VERSION 5.8 ;
BUSBITCHARS "[]" ;
DIVIDERCHAR "/" ;
UNITS
    DATABASE MICRONS 1000 ;
END UNITS

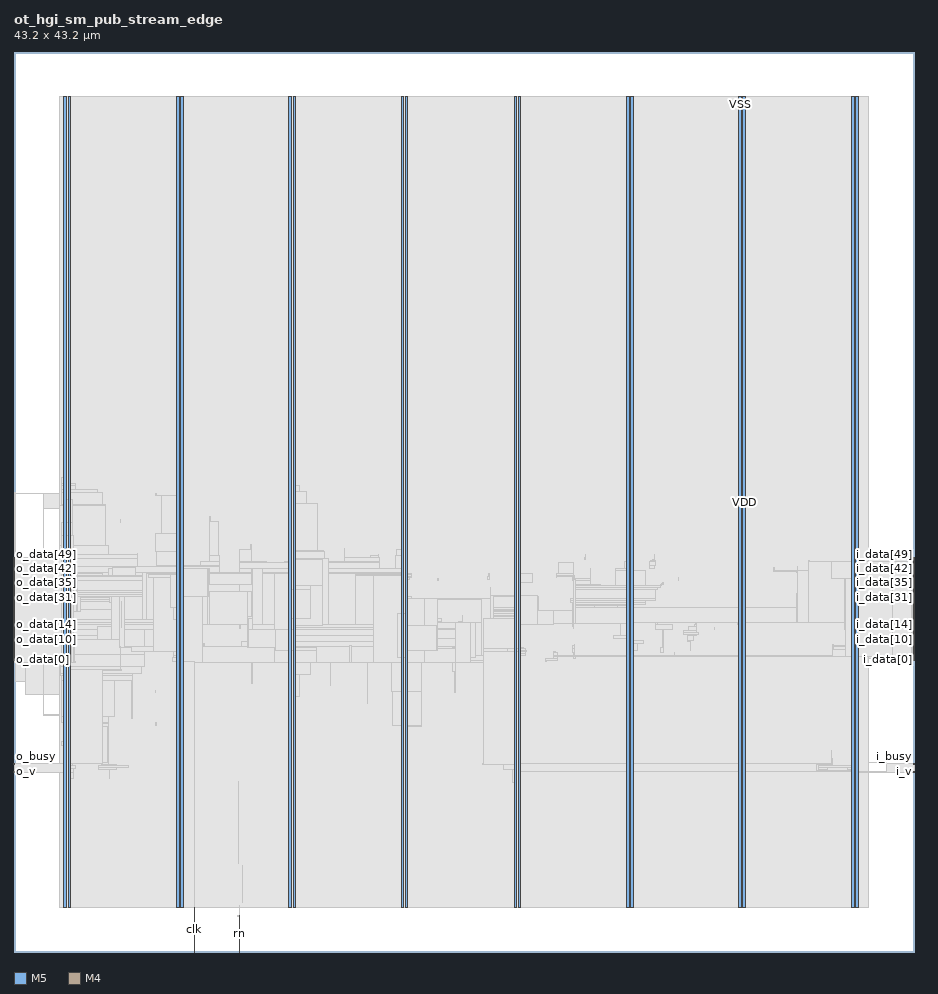
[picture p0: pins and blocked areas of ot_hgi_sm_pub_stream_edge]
MACRO ot_hgi_sm_pub_stream_edge
  FOREIGN ot_hgi_sm_pub_stream_edge 0 0 ;
  CLASS BLOCK ;
  SIZE 43.2 BY 43.2 ;
  PIN clk
    DIRECTION INPUT ;
    USE SIGNAL ;
    PORT
      LAYER M5 ;
        RECT  8.64 -0.042 8.664 0.042 ;
    END
    PORT
      LAYER M5 ;
        RECT  8.64 0.016 8.664 2.137 ;
    END
  END clk
  PIN i_busy
    DIRECTION INPUT ;
    USE SIGNAL ;
    PORT
      LAYER M4 ;
        RECT  43.158 9.024 43.242 9.048 ;
    END
  END i_busy
  PIN i_data[0]
    DIRECTION INPUT ;
    USE SIGNAL ;
    PORT
      LAYER M4 ;
        RECT  43.158 14.016 43.242 14.04 ;
    END
  END i_data[0]
  PIN i_data[10]
    DIRECTION INPUT ;
    USE SIGNAL ;
    PORT
      LAYER M4 ;
        RECT  43.158 14.976 43.242 15 ;
    END
  END i_data[10]
  PIN i_data[11]
    DIRECTION INPUT ;
    USE SIGNAL ;
    PORT
      LAYER M4 ;
        RECT  43.158 15.072 43.242 15.096 ;
    END
  END i_data[11]
  PIN i_data[12]
    DIRECTION INPUT ;
    USE SIGNAL ;
    PORT
      LAYER M4 ;
        RECT  43.158 15.168 43.242 15.192 ;
    END
  END i_data[12]
  PIN i_data[13]
    DIRECTION INPUT ;
    USE SIGNAL ;
    PORT
      LAYER M4 ;
        RECT  43.158 15.264 43.242 15.288 ;
    END
  END i_data[13]
  PIN i_data[14]
    DIRECTION INPUT ;
    USE SIGNAL ;
    PORT
      LAYER M4 ;
        RECT  43.158 15.36 43.242 15.384 ;
    END
  END i_data[14]
  PIN i_data[15]
    DIRECTION INPUT ;
    USE SIGNAL ;
    PORT
      LAYER M4 ;
        RECT  43.158 15.456 43.242 15.48 ;
    END
  END i_data[15]
  PIN i_data[16]
    DIRECTION INPUT ;
    USE SIGNAL ;
    PORT
      LAYER M4 ;
        RECT  43.158 15.552 43.242 15.576 ;
    END
  END i_data[16]
  PIN i_data[17]
    DIRECTION INPUT ;
    USE SIGNAL ;
    PORT
      LAYER M4 ;
        RECT  43.158 15.648 43.242 15.672 ;
    END
  END i_data[17]
  PIN i_data[18]
    DIRECTION INPUT ;
    USE SIGNAL ;
    PORT
      LAYER M4 ;
        RECT  43.158 15.744 43.242 15.768 ;
    END
  END i_data[18]
  PIN i_data[19]
    DIRECTION INPUT ;
    USE SIGNAL ;
    PORT
      LAYER M4 ;
        RECT  43.158 15.84 43.242 15.864 ;
    END
  END i_data[19]
  PIN i_data[1]
    DIRECTION INPUT ;
    USE SIGNAL ;
    PORT
      LAYER M4 ;
        RECT  43.158 14.112 43.242 14.136 ;
    END
  END i_data[1]
  PIN i_data[20]
    DIRECTION INPUT ;
    USE SIGNAL ;
    PORT
      LAYER M4 ;
        RECT  43.158 15.936 43.242 15.96 ;
    END
  END i_data[20]
  PIN i_data[21]
    DIRECTION INPUT ;
    USE SIGNAL ;
    PORT
      LAYER M4 ;
        RECT  43.158 16.032 43.242 16.056 ;
    END
  END i_data[21]
  PIN i_data[22]
    DIRECTION INPUT ;
    USE SIGNAL ;
    PORT
      LAYER M4 ;
        RECT  43.158 16.128 43.242 16.152 ;
    END
  END i_data[22]
  PIN i_data[23]
    DIRECTION INPUT ;
    USE SIGNAL ;
    PORT
      LAYER M4 ;
        RECT  43.158 16.224 43.242 16.248 ;
    END
  END i_data[23]
  PIN i_data[24]
    DIRECTION INPUT ;
    USE SIGNAL ;
    PORT
      LAYER M4 ;
        RECT  43.158 16.32 43.242 16.344 ;
    END
  END i_data[24]
  PIN i_data[25]
    DIRECTION INPUT ;
    USE SIGNAL ;
    PORT
      LAYER M4 ;
        RECT  43.158 16.416 43.242 16.44 ;
    END
  END i_data[25]
  PIN i_data[26]
    DIRECTION INPUT ;
    USE SIGNAL ;
    PORT
      LAYER M4 ;
        RECT  43.158 16.512 43.242 16.536 ;
    END
  END i_data[26]
  PIN i_data[27]
    DIRECTION INPUT ;
    USE SIGNAL ;
    PORT
      LAYER M4 ;
        RECT  43.158 16.608 43.242 16.632 ;
    END
  END i_data[27]
  PIN i_data[28]
    DIRECTION INPUT ;
    USE SIGNAL ;
    PORT
      LAYER M4 ;
        RECT  43.158 16.704 43.242 16.728 ;
    END
  END i_data[28]
  PIN i_data[29]
    DIRECTION INPUT ;
    USE SIGNAL ;
    PORT
      LAYER M4 ;
        RECT  43.158 16.8 43.242 16.824 ;
    END
  END i_data[29]
  PIN i_data[2]
    DIRECTION INPUT ;
    USE SIGNAL ;
    PORT
      LAYER M4 ;
        RECT  43.158 14.208 43.242 14.232 ;
    END
  END i_data[2]
  PIN i_data[30]
    DIRECTION INPUT ;
    USE SIGNAL ;
    PORT
      LAYER M4 ;
        RECT  43.158 16.896 43.242 16.92 ;
    END
  END i_data[30]
  PIN i_data[31]
    DIRECTION INPUT ;
    USE SIGNAL ;
    PORT
      LAYER M4 ;
        RECT  43.158 16.992 43.242 17.016 ;
    END
  END i_data[31]
  PIN i_data[32]
    DIRECTION INPUT ;
    USE SIGNAL ;
    PORT
      LAYER M4 ;
        RECT  43.158 17.088 43.242 17.112 ;
    END
  END i_data[32]
  PIN i_data[33]
    DIRECTION INPUT ;
    USE SIGNAL ;
    PORT
      LAYER M4 ;
        RECT  43.158 17.184 43.242 17.208 ;
    END
  END i_data[33]
  PIN i_data[34]
    DIRECTION INPUT ;
    USE SIGNAL ;
    PORT
      LAYER M4 ;
        RECT  43.158 17.28 43.242 17.304 ;
    END
  END i_data[34]
  PIN i_data[35]
    DIRECTION INPUT ;
    USE SIGNAL ;
    PORT
      LAYER M4 ;
        RECT  43.158 17.376 43.242 17.4 ;
    END
  END i_data[35]
  PIN i_data[36]
    DIRECTION INPUT ;
    USE SIGNAL ;
    PORT
      LAYER M4 ;
        RECT  43.158 17.472 43.242 17.496 ;
    END
  END i_data[36]
  PIN i_data[37]
    DIRECTION INPUT ;
    USE SIGNAL ;
    PORT
      LAYER M4 ;
        RECT  43.158 17.568 43.242 17.592 ;
    END
  END i_data[37]
  PIN i_data[38]
    DIRECTION INPUT ;
    USE SIGNAL ;
    PORT
      LAYER M4 ;
        RECT  43.158 17.664 43.242 17.688 ;
    END
  END i_data[38]
  PIN i_data[39]
    DIRECTION INPUT ;
    USE SIGNAL ;
    PORT
      LAYER M4 ;
        RECT  43.158 17.76 43.242 17.784 ;
    END
  END i_data[39]
  PIN i_data[3]
    DIRECTION INPUT ;
    USE SIGNAL ;
    PORT
      LAYER M4 ;
        RECT  43.158 14.304 43.242 14.328 ;
    END
  END i_data[3]
  PIN i_data[40]
    DIRECTION INPUT ;
    USE SIGNAL ;
    PORT
      LAYER M4 ;
        RECT  43.158 17.856 43.242 17.88 ;
    END
  END i_data[40]
  PIN i_data[41]
    DIRECTION INPUT ;
    USE SIGNAL ;
    PORT
      LAYER M4 ;
        RECT  43.158 17.952 43.242 17.976 ;
    END
  END i_data[41]
  PIN i_data[42]
    DIRECTION INPUT ;
    USE SIGNAL ;
    PORT
      LAYER M4 ;
        RECT  43.158 18.048 43.242 18.072 ;
    END
  END i_data[42]
  PIN i_data[43]
    DIRECTION INPUT ;
    USE SIGNAL ;
    PORT
      LAYER M4 ;
        RECT  43.158 18.144 43.242 18.168 ;
    END
  END i_data[43]
  PIN i_data[44]
    DIRECTION INPUT ;
    USE SIGNAL ;
    PORT
      LAYER M4 ;
        RECT  43.158 18.24 43.242 18.264 ;
    END
  END i_data[44]
  PIN i_data[45]
    DIRECTION INPUT ;
    USE SIGNAL ;
    PORT
      LAYER M4 ;
        RECT  43.158 18.336 43.242 18.36 ;
    END
  END i_data[45]
  PIN i_data[46]
    DIRECTION INPUT ;
    USE SIGNAL ;
    PORT
      LAYER M4 ;
        RECT  43.158 18.432 43.242 18.456 ;
    END
  END i_data[46]
  PIN i_data[47]
    DIRECTION INPUT ;
    USE SIGNAL ;
    PORT
      LAYER M4 ;
        RECT  43.158 18.528 43.242 18.552 ;
    END
  END i_data[47]
  PIN i_data[48]
    DIRECTION INPUT ;
    USE SIGNAL ;
    PORT
      LAYER M4 ;
        RECT  43.158 18.624 43.242 18.648 ;
    END
  END i_data[48]
  PIN i_data[49]
    DIRECTION INPUT ;
    USE SIGNAL ;
    PORT
      LAYER M4 ;
        RECT  43.158 18.72 43.242 18.744 ;
    END
  END i_data[49]
  PIN i_data[4]
    DIRECTION INPUT ;
    USE SIGNAL ;
    PORT
      LAYER M4 ;
        RECT  43.158 14.4 43.242 14.424 ;
    END
  END i_data[4]
  PIN i_data[50]
    DIRECTION INPUT ;
    USE SIGNAL ;
    PORT
      LAYER M4 ;
        RECT  43.158 18.816 43.242 18.84 ;
    END
  END i_data[50]
  PIN i_data[51]
    DIRECTION INPUT ;
    USE SIGNAL ;
    PORT
      LAYER M4 ;
        RECT  43.158 18.912 43.242 18.936 ;
    END
  END i_data[51]
  PIN i_data[5]
    DIRECTION INPUT ;
    USE SIGNAL ;
    PORT
      LAYER M4 ;
        RECT  43.158 14.496 43.242 14.52 ;
    END
  END i_data[5]
  PIN i_data[6]
    DIRECTION INPUT ;
    USE SIGNAL ;
    PORT
      LAYER M4 ;
        RECT  43.158 14.592 43.242 14.616 ;
    END
  END i_data[6]
  PIN i_data[7]
    DIRECTION INPUT ;
    USE SIGNAL ;
    PORT
      LAYER M4 ;
        RECT  43.158 14.688 43.242 14.712 ;
    END
  END i_data[7]
  PIN i_data[8]
    DIRECTION INPUT ;
    USE SIGNAL ;
    PORT
      LAYER M4 ;
        RECT  43.158 14.784 43.242 14.808 ;
    END
  END i_data[8]
  PIN i_data[9]
    DIRECTION INPUT ;
    USE SIGNAL ;
    PORT
      LAYER M4 ;
        RECT  43.158 14.88 43.242 14.904 ;
    END
  END i_data[9]
  PIN i_v
    DIRECTION INPUT ;
    USE SIGNAL ;
    PORT
      LAYER M4 ;
        RECT  43.158 8.64 43.242 8.664 ;
    END
  END i_v
  PIN o_busy
    DIRECTION OUTPUT ;
    USE SIGNAL ;
    PORT
      LAYER M4 ;
        RECT  -0.042 9.024 0.042 9.048 ;
    END
  END o_busy
  PIN o_data[0]
    DIRECTION OUTPUT ;
    USE SIGNAL ;
    PORT
      LAYER M4 ;
        RECT  -0.042 14.016 0.042 14.04 ;
    END
  END o_data[0]
  PIN o_data[10]
    DIRECTION OUTPUT ;
    USE SIGNAL ;
    PORT
      LAYER M4 ;
        RECT  -0.042 14.976 0.042 15 ;
    END
  END o_data[10]
  PIN o_data[11]
    DIRECTION OUTPUT ;
    USE SIGNAL ;
    PORT
      LAYER M4 ;
        RECT  -0.042 15.072 0.042 15.096 ;
    END
  END o_data[11]
  PIN o_data[12]
    DIRECTION OUTPUT ;
    USE SIGNAL ;
    PORT
      LAYER M4 ;
        RECT  -0.042 15.168 0.042 15.192 ;
    END
  END o_data[12]
  PIN o_data[13]
    DIRECTION OUTPUT ;
    USE SIGNAL ;
    PORT
      LAYER M4 ;
        RECT  -0.042 15.264 0.042 15.288 ;
    END
  END o_data[13]
  PIN o_data[14]
    DIRECTION OUTPUT ;
    USE SIGNAL ;
    PORT
      LAYER M4 ;
        RECT  -0.042 15.36 0.042 15.384 ;
    END
  END o_data[14]
  PIN o_data[15]
    DIRECTION OUTPUT ;
    USE SIGNAL ;
    PORT
      LAYER M4 ;
        RECT  -0.042 15.456 0.042 15.48 ;
    END
  END o_data[15]
  PIN o_data[16]
    DIRECTION OUTPUT ;
    USE SIGNAL ;
    PORT
      LAYER M4 ;
        RECT  -0.042 15.552 0.042 15.576 ;
    END
  END o_data[16]
  PIN o_data[17]
    DIRECTION OUTPUT ;
    USE SIGNAL ;
    PORT
      LAYER M4 ;
        RECT  -0.042 15.648 0.042 15.672 ;
    END
  END o_data[17]
  PIN o_data[18]
    DIRECTION OUTPUT ;
    USE SIGNAL ;
    PORT
      LAYER M4 ;
        RECT  -0.042 15.744 0.042 15.768 ;
    END
  END o_data[18]
  PIN o_data[19]
    DIRECTION OUTPUT ;
    USE SIGNAL ;
    PORT
      LAYER M4 ;
        RECT  -0.042 15.84 0.042 15.864 ;
    END
  END o_data[19]
  PIN o_data[1]
    DIRECTION OUTPUT ;
    USE SIGNAL ;
    PORT
      LAYER M4 ;
        RECT  -0.042 14.112 0.042 14.136 ;
    END
  END o_data[1]
  PIN o_data[20]
    DIRECTION OUTPUT ;
    USE SIGNAL ;
    PORT
      LAYER M4 ;
        RECT  -0.042 15.936 0.042 15.96 ;
    END
  END o_data[20]
  PIN o_data[21]
    DIRECTION OUTPUT ;
    USE SIGNAL ;
    PORT
      LAYER M4 ;
        RECT  -0.042 16.032 0.042 16.056 ;
    END
  END o_data[21]
  PIN o_data[22]
    DIRECTION OUTPUT ;
    USE SIGNAL ;
    PORT
      LAYER M4 ;
        RECT  -0.042 16.128 0.042 16.152 ;
    END
  END o_data[22]
  PIN o_data[23]
    DIRECTION OUTPUT ;
    USE SIGNAL ;
    PORT
      LAYER M4 ;
        RECT  -0.042 16.224 0.042 16.248 ;
    END
  END o_data[23]
  PIN o_data[24]
    DIRECTION OUTPUT ;
    USE SIGNAL ;
    PORT
      LAYER M4 ;
        RECT  -0.042 16.32 0.042 16.344 ;
    END
  END o_data[24]
  PIN o_data[25]
    DIRECTION OUTPUT ;
    USE SIGNAL ;
    PORT
      LAYER M4 ;
        RECT  -0.042 16.416 0.042 16.44 ;
    END
  END o_data[25]
  PIN o_data[26]
    DIRECTION OUTPUT ;
    USE SIGNAL ;
    PORT
      LAYER M4 ;
        RECT  -0.042 16.512 0.042 16.536 ;
    END
  END o_data[26]
  PIN o_data[27]
    DIRECTION OUTPUT ;
    USE SIGNAL ;
    PORT
      LAYER M4 ;
        RECT  -0.042 16.608 0.042 16.632 ;
    END
  END o_data[27]
  PIN o_data[28]
    DIRECTION OUTPUT ;
    USE SIGNAL ;
    PORT
      LAYER M4 ;
        RECT  -0.042 16.704 0.042 16.728 ;
    END
  END o_data[28]
  PIN o_data[29]
    DIRECTION OUTPUT ;
    USE SIGNAL ;
    PORT
      LAYER M4 ;
        RECT  -0.042 16.8 0.042 16.824 ;
    END
  END o_data[29]
  PIN o_data[2]
    DIRECTION OUTPUT ;
    USE SIGNAL ;
    PORT
      LAYER M4 ;
        RECT  -0.042 14.208 0.042 14.232 ;
    END
  END o_data[2]
  PIN o_data[30]
    DIRECTION OUTPUT ;
    USE SIGNAL ;
    PORT
      LAYER M4 ;
        RECT  -0.042 16.896 0.042 16.92 ;
    END
  END o_data[30]
  PIN o_data[31]
    DIRECTION OUTPUT ;
    USE SIGNAL ;
    PORT
      LAYER M4 ;
        RECT  -0.042 16.992 0.042 17.016 ;
    END
  END o_data[31]
  PIN o_data[32]
    DIRECTION OUTPUT ;
    USE SIGNAL ;
    PORT
      LAYER M4 ;
        RECT  -0.042 17.088 0.042 17.112 ;
    END
  END o_data[32]
  PIN o_data[33]
    DIRECTION OUTPUT ;
    USE SIGNAL ;
    PORT
      LAYER M4 ;
        RECT  -0.042 17.184 0.042 17.208 ;
    END
  END o_data[33]
  PIN o_data[34]
    DIRECTION OUTPUT ;
    USE SIGNAL ;
    PORT
      LAYER M4 ;
        RECT  -0.042 17.28 0.042 17.304 ;
    END
  END o_data[34]
  PIN o_data[35]
    DIRECTION OUTPUT ;
    USE SIGNAL ;
    PORT
      LAYER M4 ;
        RECT  -0.042 17.376 0.042 17.4 ;
    END
  END o_data[35]
  PIN o_data[36]
    DIRECTION OUTPUT ;
    USE SIGNAL ;
    PORT
      LAYER M4 ;
        RECT  -0.042 17.472 0.042 17.496 ;
    END
  END o_data[36]
  PIN o_data[37]
    DIRECTION OUTPUT ;
    USE SIGNAL ;
    PORT
      LAYER M4 ;
        RECT  -0.042 17.568 0.042 17.592 ;
    END
  END o_data[37]
  PIN o_data[38]
    DIRECTION OUTPUT ;
    USE SIGNAL ;
    PORT
      LAYER M4 ;
        RECT  -0.042 17.664 0.042 17.688 ;
    END
  END o_data[38]
  PIN o_data[39]
    DIRECTION OUTPUT ;
    USE SIGNAL ;
    PORT
      LAYER M4 ;
        RECT  -0.042 17.76 0.042 17.784 ;
    END
  END o_data[39]
  PIN o_data[3]
    DIRECTION OUTPUT ;
    USE SIGNAL ;
    PORT
      LAYER M4 ;
        RECT  -0.042 14.304 0.042 14.328 ;
    END
  END o_data[3]
  PIN o_data[40]
    DIRECTION OUTPUT ;
    USE SIGNAL ;
    PORT
      LAYER M4 ;
        RECT  -0.042 17.856 0.042 17.88 ;
    END
  END o_data[40]
  PIN o_data[41]
    DIRECTION OUTPUT ;
    USE SIGNAL ;
    PORT
      LAYER M4 ;
        RECT  -0.042 17.952 0.042 17.976 ;
    END
  END o_data[41]
  PIN o_data[42]
    DIRECTION OUTPUT ;
    USE SIGNAL ;
    PORT
      LAYER M4 ;
        RECT  -0.042 18.048 0.042 18.072 ;
    END
  END o_data[42]
  PIN o_data[43]
    DIRECTION OUTPUT ;
    USE SIGNAL ;
    PORT
      LAYER M4 ;
        RECT  -0.042 18.144 0.042 18.168 ;
    END
  END o_data[43]
  PIN o_data[44]
    DIRECTION OUTPUT ;
    USE SIGNAL ;
    PORT
      LAYER M4 ;
        RECT  -0.042 18.24 0.042 18.264 ;
    END
  END o_data[44]
  PIN o_data[45]
    DIRECTION OUTPUT ;
    USE SIGNAL ;
    PORT
      LAYER M4 ;
        RECT  -0.042 18.336 0.042 18.36 ;
    END
  END o_data[45]
  PIN o_data[46]
    DIRECTION OUTPUT ;
    USE SIGNAL ;
    PORT
      LAYER M4 ;
        RECT  -0.042 18.432 0.042 18.456 ;
    END
  END o_data[46]
  PIN o_data[47]
    DIRECTION OUTPUT ;
    USE SIGNAL ;
    PORT
      LAYER M4 ;
        RECT  -0.042 18.528 0.042 18.552 ;
    END
  END o_data[47]
  PIN o_data[48]
    DIRECTION OUTPUT ;
    USE SIGNAL ;
    PORT
      LAYER M4 ;
        RECT  -0.042 18.624 0.042 18.648 ;
    END
  END o_data[48]
  PIN o_data[49]
    DIRECTION OUTPUT ;
    USE SIGNAL ;
    PORT
      LAYER M4 ;
        RECT  -0.042 18.72 0.042 18.744 ;
    END
  END o_data[49]
  PIN o_data[4]
    DIRECTION OUTPUT ;
    USE SIGNAL ;
    PORT
      LAYER M4 ;
        RECT  -0.042 14.4 0.042 14.424 ;
    END
  END o_data[4]
  PIN o_data[50]
    DIRECTION OUTPUT ;
    USE SIGNAL ;
    PORT
      LAYER M4 ;
        RECT  -0.042 18.816 0.042 18.84 ;
    END
  END o_data[50]
  PIN o_data[51]
    DIRECTION OUTPUT ;
    USE SIGNAL ;
    PORT
      LAYER M4 ;
        RECT  -0.042 18.912 0.042 18.936 ;
    END
  END o_data[51]
  PIN o_data[5]
    DIRECTION OUTPUT ;
    USE SIGNAL ;
    PORT
      LAYER M4 ;
        RECT  -0.042 14.496 0.042 14.52 ;
    END
  END o_data[5]
  PIN o_data[6]
    DIRECTION OUTPUT ;
    USE SIGNAL ;
    PORT
      LAYER M4 ;
        RECT  -0.042 14.592 0.042 14.616 ;
    END
  END o_data[6]
  PIN o_data[7]
    DIRECTION OUTPUT ;
    USE SIGNAL ;
    PORT
      LAYER M4 ;
        RECT  -0.042 14.688 0.042 14.712 ;
    END
  END o_data[7]
  PIN o_data[8]
    DIRECTION OUTPUT ;
    USE SIGNAL ;
    PORT
      LAYER M4 ;
        RECT  -0.042 14.784 0.042 14.808 ;
    END
  END o_data[8]
  PIN o_data[9]
    DIRECTION OUTPUT ;
    USE SIGNAL ;
    PORT
      LAYER M4 ;
        RECT  -0.042 14.88 0.042 14.904 ;
    END
  END o_data[9]
  PIN o_v
    DIRECTION OUTPUT ;
    USE SIGNAL ;
    PORT
      LAYER M4 ;
        RECT  -0.042 8.64 0.042 8.664 ;
    END
  END o_v
  PIN rn
    DIRECTION INPUT ;
    USE SIGNAL ;
    PORT
      LAYER M5 ;
        RECT  10.8 -0.042 10.824 0.042 ;
    END
    PORT
      LAYER M5 ;
        RECT  10.8 0.016 10.824 1.763 ;
    END
  END rn
  PIN VDD
    DIRECTION INOUT ;
    USE POWER ;
    PORT
      LAYER M5 ;
        RECT  40.392 2.151 40.512 41.049 ;
        RECT  34.992 2.151 35.112 41.049 ;
        RECT  29.592 2.151 29.712 41.049 ;
        RECT  24.192 2.151 24.312 41.049 ;
        RECT  18.792 2.151 18.912 41.049 ;
        RECT  13.392 2.151 13.512 41.049 ;
        RECT  7.992 2.151 8.112 41.049 ;
        RECT  2.592 2.151 2.712 41.049 ;
    END
  END VDD
  PIN VSS
    DIRECTION INOUT ;
    USE GROUND ;
    PORT
      LAYER M5 ;
        RECT  40.2 2.137 40.32 41.063 ;
        RECT  34.8 2.137 34.92 41.063 ;
        RECT  29.4 2.137 29.52 41.063 ;
        RECT  24 2.137 24.12 41.063 ;
        RECT  18.6 2.137 18.72 41.063 ;
        RECT  13.2 2.137 13.32 41.063 ;
        RECT  7.8 2.137 7.92 41.063 ;
        RECT  2.4 2.137 2.52 41.063 ;
    END
  END VSS
  # OT_OBS_CLOSED layer=M5 d_um=1.536 added=14
  OBS
    LAYER RVTN ;
     RECT  2.16 2.16 41.04 2.295 ;
     RECT  2.16 2.565 41.04 2.835 ;
     RECT  2.16 3.105 41.04 3.375 ;
     RECT  2.16 3.645 41.04 3.915 ;
     RECT  2.16 4.185 41.04 4.455 ;
     RECT  2.16 4.725 41.04 4.995 ;
     RECT  2.16 5.265 41.04 5.535 ;
     RECT  2.16 5.805 41.04 6.075 ;
     RECT  2.16 6.345 41.04 6.615 ;
     RECT  2.16 6.885 41.04 7.155 ;
     RECT  2.16 7.425 41.04 7.695 ;
     RECT  2.16 7.965 41.04 8.235 ;
     RECT  2.16 8.505 41.04 8.775 ;
     RECT  2.16 9.045 41.04 9.315 ;
     RECT  2.16 9.585 41.04 9.855 ;
     RECT  2.16 10.125 41.04 10.395 ;
     RECT  2.16 10.665 41.04 10.935 ;
     RECT  2.16 11.205 41.04 11.475 ;
     RECT  2.16 11.745 41.04 12.015 ;
     RECT  2.16 12.285 41.04 12.555 ;
     RECT  2.16 12.825 41.04 13.095 ;
     RECT  2.16 13.365 41.04 13.635 ;
     RECT  2.16 13.905 41.04 14.175 ;
     RECT  2.16 14.445 41.04 14.715 ;
     RECT  2.16 14.985 41.04 15.255 ;
     RECT  2.16 15.525 41.04 15.795 ;
     RECT  2.16 16.065 41.04 16.335 ;
     RECT  2.16 16.605 41.04 16.875 ;
     RECT  2.16 17.145 41.04 17.415 ;
     RECT  2.16 17.685 41.04 17.955 ;
     RECT  2.16 18.225 41.04 18.495 ;
     RECT  2.16 18.765 41.04 19.035 ;
     RECT  2.16 19.305 41.04 19.575 ;
     RECT  2.16 19.845 41.04 20.115 ;
     RECT  2.16 20.385 41.04 20.655 ;
     RECT  2.16 20.925 41.04 21.195 ;
     RECT  2.16 21.465 41.04 21.735 ;
     RECT  2.16 22.005 41.04 22.275 ;
     RECT  2.16 22.545 41.04 22.815 ;
     RECT  2.16 23.085 41.04 23.355 ;
     RECT  2.16 23.625 41.04 23.895 ;
     RECT  2.16 24.165 41.04 24.435 ;
     RECT  2.16 24.705 41.04 24.975 ;
     RECT  2.16 25.245 41.04 25.515 ;
     RECT  2.16 25.785 41.04 26.055 ;
     RECT  2.16 26.325 41.04 26.595 ;
     RECT  2.16 26.865 41.04 27.135 ;
     RECT  2.16 27.405 41.04 27.675 ;
     RECT  2.16 27.945 41.04 28.215 ;
     RECT  2.16 28.485 41.04 28.755 ;
     RECT  2.16 29.025 41.04 29.295 ;
     RECT  2.16 29.565 41.04 29.835 ;
     RECT  2.16 30.105 41.04 30.375 ;
     RECT  2.16 30.645 41.04 30.915 ;
     RECT  2.16 31.185 41.04 31.455 ;
     RECT  2.16 31.725 41.04 31.995 ;
     RECT  2.16 32.265 41.04 32.535 ;
     RECT  2.16 32.805 41.04 33.075 ;
     RECT  2.16 33.345 41.04 33.615 ;
     RECT  2.16 33.885 41.04 34.155 ;
     RECT  2.16 34.425 41.04 34.695 ;
     RECT  2.16 34.965 41.04 35.235 ;
     RECT  2.16 35.505 41.04 35.775 ;
     RECT  2.16 36.045 41.04 36.315 ;
     RECT  2.16 36.585 41.04 36.855 ;
     RECT  2.16 37.125 41.04 37.395 ;
     RECT  2.16 37.665 41.04 37.935 ;
     RECT  2.16 38.205 41.04 38.475 ;
     RECT  2.16 38.745 41.04 39.015 ;
     RECT  2.16 39.285 41.04 39.555 ;
     RECT  2.16 39.825 41.04 40.095 ;
     RECT  2.16 40.365 41.04 40.635 ;
     RECT  2.16 40.905 41.04 41.04 ;
    LAYER RVTP ;
     RECT  2.16 2.295 41.04 2.565 ;
     RECT  2.16 2.835 41.04 3.105 ;
     RECT  2.16 3.375 41.04 3.645 ;
     RECT  2.16 3.915 41.04 4.185 ;
     RECT  2.16 4.455 41.04 4.725 ;
     RECT  2.16 4.995 41.04 5.265 ;
     RECT  2.16 5.535 41.04 5.805 ;
     RECT  2.16 6.075 41.04 6.345 ;
     RECT  2.16 6.615 41.04 6.885 ;
     RECT  2.16 7.155 41.04 7.425 ;
     RECT  2.16 7.695 41.04 7.965 ;
     RECT  2.16 8.235 41.04 8.505 ;
     RECT  2.16 8.775 41.04 9.045 ;
     RECT  2.16 9.315 41.04 9.585 ;
     RECT  2.16 9.855 41.04 10.125 ;
     RECT  2.16 10.395 41.04 10.665 ;
     RECT  2.16 10.935 41.04 11.205 ;
     RECT  2.16 11.475 41.04 11.745 ;
     RECT  2.16 12.015 41.04 12.285 ;
     RECT  2.16 12.555 41.04 12.825 ;
     RECT  2.16 13.095 41.04 13.365 ;
     RECT  2.16 13.635 41.04 13.905 ;
     RECT  2.16 14.175 41.04 14.445 ;
     RECT  2.16 14.715 41.04 14.985 ;
     RECT  2.16 15.255 41.04 15.525 ;
     RECT  2.16 15.795 41.04 16.065 ;
     RECT  2.16 16.335 41.04 16.605 ;
     RECT  2.16 16.875 41.04 17.145 ;
     RECT  2.16 17.415 41.04 17.685 ;
     RECT  2.16 17.955 41.04 18.225 ;
     RECT  2.16 18.495 41.04 18.765 ;
     RECT  2.16 19.035 41.04 19.305 ;
     RECT  2.16 19.575 41.04 19.845 ;
     RECT  2.16 20.115 41.04 20.385 ;
     RECT  2.16 20.655 41.04 20.925 ;
     RECT  2.16 21.195 41.04 21.465 ;
     RECT  2.16 21.735 41.04 22.005 ;
     RECT  2.16 22.275 41.04 22.545 ;
     RECT  2.16 22.815 41.04 23.085 ;
     RECT  2.16 23.355 41.04 23.625 ;
     RECT  2.16 23.895 41.04 24.165 ;
     RECT  2.16 24.435 41.04 24.705 ;
     RECT  2.16 24.975 41.04 25.245 ;
     RECT  2.16 25.515 41.04 25.785 ;
     RECT  2.16 26.055 41.04 26.325 ;
     RECT  2.16 26.595 41.04 26.865 ;
     RECT  2.16 27.135 41.04 27.405 ;
     RECT  2.16 27.675 41.04 27.945 ;
     RECT  2.16 28.215 41.04 28.485 ;
     RECT  2.16 28.755 41.04 29.025 ;
     RECT  2.16 29.295 41.04 29.565 ;
     RECT  2.16 29.835 41.04 30.105 ;
     RECT  2.16 30.375 41.04 30.645 ;
     RECT  2.16 30.915 41.04 31.185 ;
     RECT  2.16 31.455 41.04 31.725 ;
     RECT  2.16 31.995 41.04 32.265 ;
     RECT  2.16 32.535 41.04 32.805 ;
     RECT  2.16 33.075 41.04 33.345 ;
     RECT  2.16 33.615 41.04 33.885 ;
     RECT  2.16 34.155 41.04 34.425 ;
     RECT  2.16 34.695 41.04 34.965 ;
     RECT  2.16 35.235 41.04 35.505 ;
     RECT  2.16 35.775 41.04 36.045 ;
     RECT  2.16 36.315 41.04 36.585 ;
     RECT  2.16 36.855 41.04 37.125 ;
     RECT  2.16 37.395 41.04 37.665 ;
     RECT  2.16 37.935 41.04 38.205 ;
     RECT  2.16 38.475 41.04 38.745 ;
     RECT  2.16 39.015 41.04 39.285 ;
     RECT  2.16 39.555 41.04 39.825 ;
     RECT  2.16 40.095 41.04 40.365 ;
     RECT  2.16 40.635 41.04 40.905 ;
    LAYER M1 ;
     RECT  2.16 2.151 41.04 41.049 ;
    LAYER M2 ;
     RECT  0.031 14.22 0.067 14.544 ;
     RECT  0.031 15.606 0.067 15.624 ;
     RECT  0.067 12.996 0.103 13.014 ;
     RECT  0.067 14.22 0.103 15.624 ;
     RECT  0.103 12.996 0.535 15.624 ;
     RECT  0.031 16.884 0.535 17.604 ;
     RECT  0.031 22.014 1.399 22.032 ;
     RECT  1.399 11.376 2.16 11.394 ;
     RECT  0.535 12.366 2.16 17.604 ;
     RECT  1.723 18.846 2.16 18.864 ;
     RECT  1.399 21.276 2.16 22.032 ;
     RECT  2.16 2.151 41.04 41.049 ;
     RECT  41.04 9.09 41.891 9.108 ;
     RECT  41.04 14.076 42.179 18.99 ;
     RECT  42.179 14.076 42.215 14.634 ;
     RECT  42.179 16.038 42.215 17.37 ;
     RECT  42.215 16.038 43.051 17.1 ;
     RECT  42.179 18.126 43.051 18.99 ;
     RECT  43.051 16.038 43.115 18.99 ;
     RECT  42.215 14.112 43.151 14.634 ;
     RECT  43.115 16.776 43.151 16.794 ;
     RECT  43.115 17.586 43.151 18.99 ;
    LAYER M3 ;
     RECT  10.8 1.723 10.818 2.255 ;
     RECT  2.415 2.143 2.505 2.413 ;
     RECT  7.815 2.143 7.905 2.413 ;
     RECT  13.215 2.143 13.305 2.413 ;
     RECT  18.615 2.143 18.705 2.413 ;
     RECT  24.015 2.143 24.105 2.413 ;
     RECT  29.415 2.143 29.505 2.413 ;
     RECT  34.815 2.143 34.905 2.413 ;
     RECT  40.215 2.143 40.305 2.413 ;
     RECT  10.944 2.371 10.962 4.145 ;
     RECT  24.015 2.413 24.297 8.131 ;
     RECT  10.764 4.261 10.782 8.195 ;
     RECT  2.415 2.413 2.697 8.311 ;
     RECT  2.415 8.311 2.862 8.635 ;
     RECT  34.815 2.413 35.097 8.671 ;
     RECT  40.215 2.413 40.497 8.671 ;
     RECT  34.704 8.671 35.097 8.717 ;
     RECT  30.78 8.671 30.798 8.771 ;
     RECT  4.572 8.311 4.59 8.779 ;
     RECT  23.94 8.131 24.297 8.779 ;
     RECT  39.024 8.671 39.042 8.779 ;
     RECT  40.104 8.671 40.497 8.779 ;
     RECT  2.304 8.635 2.862 8.807 ;
     RECT  2.415 8.807 2.862 8.815 ;
     RECT  4.068 8.779 4.914 8.851 ;
     RECT  38.628 8.779 39.042 8.851 ;
     RECT  39.996 8.779 40.497 8.851 ;
     RECT  2.415 8.815 2.97 8.969 ;
     RECT  4.068 8.851 5.49 8.969 ;
     RECT  38.628 8.851 40.497 8.969 ;
     RECT  38.628 8.969 39.294 8.977 ;
     RECT  4.176 8.969 4.914 9.005 ;
     RECT  25.2 8.671 25.218 9.041 ;
     RECT  38.484 8.977 39.294 9.041 ;
     RECT  38.484 9.041 38.502 9.053 ;
     RECT  4.176 9.005 4.518 9.101 ;
     RECT  41.868 9.019 41.886 9.113 ;
     RECT  39.24 9.041 39.294 9.275 ;
     RECT  39.24 9.275 39.258 9.689 ;
     RECT  2.415 8.969 2.79 9.931 ;
     RECT  2.304 9.931 2.79 10.085 ;
     RECT  2.415 10.085 2.79 10.471 ;
     RECT  2.415 10.471 2.826 10.705 ;
     RECT  2.415 10.705 2.862 10.741 ;
     RECT  2.415 10.741 2.934 10.831 ;
     RECT  4.5 9.101 4.518 10.831 ;
     RECT  18.615 2.413 18.897 10.831 ;
     RECT  18.615 10.831 19.566 10.867 ;
     RECT  3.96 10.831 4.518 10.975 ;
     RECT  2.376 10.831 2.934 11.011 ;
     RECT  3.96 10.975 4.554 11.011 ;
     RECT  6.804 10.867 6.822 11.039 ;
     RECT  2.304 11.011 4.554 11.281 ;
     RECT  13.215 2.413 13.497 12.253 ;
     RECT  18.18 10.867 19.566 12.487 ;
     RECT  6.768 12.451 6.786 12.551 ;
     RECT  0.54 12.361 0.558 12.991 ;
     RECT  2.304 11.281 4.842 13.027 ;
     RECT  5.652 11.209 5.67 13.027 ;
     RECT  2.304 13.027 5.67 13.261 ;
     RECT  13.215 12.253 13.698 13.333 ;
     RECT  2.232 13.261 5.706 13.369 ;
     RECT  21.168 12.451 21.186 13.441 ;
     RECT  2.232 13.369 6.102 13.711 ;
     RECT  7.815 2.413 8.097 13.873 ;
     RECT  0.072 12.991 0.558 13.915 ;
     RECT  21.024 13.441 21.186 13.915 ;
     RECT  22.536 13.027 22.554 13.915 ;
     RECT  7.815 13.873 8.802 13.945 ;
     RECT  18.108 12.487 19.566 13.981 ;
     RECT  21.024 13.915 22.554 13.981 ;
     RECT  23.508 8.779 24.297 13.981 ;
     RECT  25.524 13.945 25.542 13.981 ;
     RECT  13.215 13.333 14.238 14.071 ;
     RECT  15.192 12.793 15.21 14.071 ;
     RECT  25.524 13.981 26.082 14.099 ;
     RECT  26.928 14.071 26.946 14.107 ;
     RECT  7.596 13.945 8.802 14.135 ;
     RECT  42.192 14.071 42.21 14.141 ;
     RECT  11.412 12.901 11.43 14.143 ;
     RECT  0.036 13.915 0.558 14.237 ;
     RECT  7.668 14.135 8.802 14.243 ;
     RECT  26.856 14.107 26.946 14.243 ;
     RECT  15.984 14.215 16.002 14.251 ;
     RECT  16.956 11.911 16.974 14.251 ;
     RECT  21.024 13.981 24.297 14.251 ;
     RECT  2.232 13.711 6.282 14.279 ;
     RECT  21.024 14.251 24.534 14.341 ;
     RECT  13.215 14.071 15.21 14.347 ;
     RECT  25.884 14.099 26.082 14.369 ;
     RECT  31.68 14.251 31.698 14.369 ;
     RECT  12.708 14.347 15.21 14.377 ;
     RECT  15.984 14.251 16.974 14.377 ;
     RECT  26.856 14.243 26.91 14.377 ;
     RECT  12.708 14.377 17.262 14.395 ;
     RECT  25.884 14.369 25.974 14.405 ;
     RECT  25.884 14.405 25.902 14.441 ;
     RECT  29.415 2.413 29.697 14.449 ;
     RECT  10.836 14.143 11.43 14.477 ;
     RECT  21.024 14.341 24.57 14.477 ;
     RECT  12.636 14.395 17.262 14.485 ;
     RECT  21.024 14.477 24.534 14.549 ;
     RECT  26.784 14.377 26.91 14.549 ;
     RECT  10.908 14.477 11.43 14.635 ;
     RECT  12.42 14.485 17.262 14.635 ;
     RECT  21.024 14.549 24.462 14.639 ;
     RECT  31.032 14.377 31.158 14.639 ;
     RECT  43.128 14.011 43.146 14.639 ;
     RECT  10.908 14.635 17.262 14.647 ;
     RECT  18.108 13.981 20.07 14.647 ;
     RECT  21.024 14.639 24.297 14.647 ;
     RECT  7.668 14.243 8.19 14.669 ;
     RECT  39.312 14.491 39.33 14.677 ;
     RECT  40.215 8.969 40.497 14.677 ;
     RECT  26.82 14.549 26.91 14.711 ;
     RECT  39.312 14.677 40.497 14.717 ;
     RECT  39.312 14.717 39.33 14.747 ;
     RECT  40.215 14.717 40.497 14.779 ;
     RECT  26.892 14.711 26.91 14.783 ;
     RECT  29.415 14.449 29.934 14.791 ;
     RECT  9.108 14.449 9.126 14.819 ;
     RECT  10.908 14.647 17.334 14.909 ;
     RECT  32.472 14.485 32.49 14.917 ;
     RECT  29.415 14.791 30.222 14.945 ;
     RECT  32.328 14.917 32.49 14.953 ;
     RECT  40.215 14.779 41.022 14.971 ;
     RECT  42.156 14.587 42.174 14.971 ;
     RECT  1.404 11.371 1.422 15.005 ;
     RECT  29.415 14.945 29.697 15.025 ;
     RECT  1.44 15.019 1.53 15.059 ;
     RECT  0.036 14.237 0.162 15.061 ;
     RECT  18.108 14.647 24.297 15.061 ;
     RECT  1.44 15.059 1.458 15.101 ;
     RECT  34.815 8.717 35.097 15.151 ;
     RECT  12.096 14.909 17.334 15.179 ;
     RECT  28.764 15.025 29.697 15.179 ;
     RECT  32.328 14.953 32.634 15.187 ;
     RECT  32.328 15.187 32.778 15.223 ;
     RECT  32.112 15.223 32.85 15.323 ;
     RECT  7.776 14.669 8.19 15.421 ;
     RECT  32.112 15.323 32.742 15.449 ;
     RECT  2.304 14.279 6.282 15.457 ;
     RECT  7.416 15.421 8.226 15.457 ;
     RECT  12.564 15.179 17.334 15.457 ;
     RECT  18.072 15.061 24.297 15.457 ;
     RECT  31.14 14.639 31.158 15.457 ;
     RECT  40.215 14.971 42.174 15.485 ;
     RECT  40.215 15.485 42.066 15.499 ;
     RECT  33.624 15.457 33.642 15.557 ;
     RECT  12.564 15.457 24.297 15.581 ;
     RECT  39.852 15.499 42.066 15.593 ;
     RECT  26.856 15.529 26.874 15.601 ;
     RECT  32.364 15.449 32.742 15.629 ;
     RECT  43.056 15.499 43.074 15.643 ;
     RECT  12.564 15.581 21.582 15.719 ;
     RECT  30.78 15.457 31.59 15.719 ;
     RECT  32.652 15.629 32.742 15.719 ;
     RECT  2.304 15.457 8.226 15.727 ;
     RECT  34.776 15.151 35.097 15.727 ;
     RECT  15.66 15.719 21.582 15.755 ;
     RECT  42.948 15.643 43.074 15.773 ;
     RECT  15.66 15.755 21.546 15.791 ;
     RECT  32.724 15.719 32.742 15.791 ;
     RECT  41.58 15.593 42.066 15.791 ;
     RECT  2.304 15.727 8.262 15.799 ;
     RECT  9 15.499 9.018 15.799 ;
     RECT  10.836 15.529 10.854 15.835 ;
     RECT  26.784 15.601 26.874 15.835 ;
     RECT  39.852 15.593 40.59 15.835 ;
     RECT  15.66 15.791 20.538 15.863 ;
     RECT  21.312 15.791 21.546 15.863 ;
     RECT  30.78 15.719 30.87 15.863 ;
     RECT  34.704 15.727 35.097 15.863 ;
     RECT  30.852 15.863 30.87 15.899 ;
     RECT  39.744 15.835 40.59 15.899 ;
     RECT  2.304 15.799 9.018 15.961 ;
     RECT  10.512 15.835 10.854 15.961 ;
     RECT  12.564 15.719 14.922 15.961 ;
     RECT  40.215 15.899 40.59 15.965 ;
     RECT  10.404 15.961 10.854 15.979 ;
     RECT  11.916 15.961 14.922 15.979 ;
     RECT  17.424 15.863 20.538 15.989 ;
     RECT  25.848 15.739 25.866 15.989 ;
     RECT  17.424 15.989 20.322 16.013 ;
     RECT  22.464 15.581 24.297 16.013 ;
     RECT  43.02 15.773 43.074 16.024 ;
     RECT  26.784 15.835 27.054 16.033 ;
     RECT  22.608 16.013 24.297 16.105 ;
     RECT  29.088 15.179 29.697 16.105 ;
     RECT  17.424 16.013 20.142 16.133 ;
     RECT  21.528 15.863 21.546 16.133 ;
     RECT  22.608 16.105 24.966 16.141 ;
     RECT  0.036 15.061 0.558 16.157 ;
     RECT  10.404 15.979 14.922 16.157 ;
     RECT  43.02 16.024 43.11 16.22 ;
     RECT  42.048 15.791 42.066 16.231 ;
     RECT  18.036 16.133 20.142 16.259 ;
     RECT  22.608 16.141 25.578 16.259 ;
     RECT  19.98 16.259 20.142 16.295 ;
     RECT  43.056 16.22 43.11 16.295 ;
     RECT  18.036 16.259 19.134 16.367 ;
     RECT  22.644 16.259 25.578 16.367 ;
     RECT  20.052 16.295 20.142 16.403 ;
     RECT  22.644 16.367 25.182 16.403 ;
     RECT  42.048 16.231 42.21 16.403 ;
     RECT  2.304 15.961 9.666 16.439 ;
     RECT  22.68 16.403 25.182 16.439 ;
     RECT  42.12 16.403 42.21 16.439 ;
     RECT  26.784 16.033 27.126 16.507 ;
     RECT  27.864 16.339 27.882 16.507 ;
     RECT  22.824 16.439 25.182 16.529 ;
     RECT  13.215 16.157 14.922 16.537 ;
     RECT  15.66 15.863 16.686 16.537 ;
     RECT  43.092 16.295 43.11 16.603 ;
     RECT  0.144 16.157 0.558 16.637 ;
     RECT  26.784 16.507 27.882 16.645 ;
     RECT  28.98 16.105 29.697 16.645 ;
     RECT  26.784 16.645 29.697 16.681 ;
     RECT  26.784 16.681 30.294 16.771 ;
     RECT  13.215 16.537 16.686 16.795 ;
     RECT  43.092 16.603 43.146 16.799 ;
     RECT  2.34 16.439 9.666 16.807 ;
     RECT  10.404 16.157 12.474 16.807 ;
     RECT  0.144 16.637 0.27 16.879 ;
     RECT  26.712 16.771 30.294 16.879 ;
     RECT  40.215 15.965 40.497 16.891 ;
     RECT  2.34 16.807 12.474 16.907 ;
     RECT  22.824 16.529 22.95 16.979 ;
     RECT  26.712 16.879 30.798 16.979 ;
     RECT  38.736 16.939 38.754 16.979 ;
     RECT  2.34 16.907 9.558 17.069 ;
     RECT  18.036 16.367 19.098 17.069 ;
     RECT  25.092 16.529 25.182 17.069 ;
     RECT  18.036 17.069 18.897 17.077 ;
     RECT  10.368 16.907 12.474 17.113 ;
     RECT  13.215 16.795 17.154 17.113 ;
     RECT  0.036 16.879 0.27 17.117 ;
     RECT  22.86 16.979 22.914 17.117 ;
     RECT  25.092 17.069 25.11 17.117 ;
     RECT  10.368 17.113 17.154 17.149 ;
     RECT  17.964 17.077 18.897 17.149 ;
     RECT  2.34 17.069 9.414 17.179 ;
     RECT  2.304 17.179 9.414 17.275 ;
     RECT  2.268 17.275 9.414 17.347 ;
     RECT  42.192 16.439 42.21 17.405 ;
     RECT  37.584 17.179 37.602 17.411 ;
     RECT  26.856 16.979 30.798 17.419 ;
     RECT  26.856 17.419 30.906 17.491 ;
     RECT  22.86 17.117 22.878 17.519 ;
     RECT  43.092 16.799 43.11 17.563 ;
     RECT  26.856 17.491 31.05 17.581 ;
     RECT  43.092 17.563 43.146 17.581 ;
     RECT  26.856 17.581 31.086 17.609 ;
     RECT  26.856 17.609 28.134 17.645 ;
     RECT  31.032 17.609 31.086 17.645 ;
     RECT  37.62 17.581 37.638 17.645 ;
     RECT  42.156 17.467 42.174 17.645 ;
     RECT  31.068 17.645 31.086 17.653 ;
     RECT  40.215 16.891 41.022 17.653 ;
     RECT  31.068 17.653 31.158 17.681 ;
     RECT  0.036 17.117 0.126 17.693 ;
     RECT  40.215 17.653 41.058 17.693 ;
     RECT  24.015 16.529 24.297 17.725 ;
     RECT  31.14 17.681 31.158 17.753 ;
     RECT  26.856 17.645 27.666 17.845 ;
     RECT  2.196 17.347 9.414 17.851 ;
     RECT  10.368 17.149 18.897 17.887 ;
     RECT  39.312 17.851 39.33 17.947 ;
     RECT  43.056 17.581 43.146 17.947 ;
     RECT  20.34 17.851 20.358 17.951 ;
     RECT  26.82 17.845 27.666 17.951 ;
     RECT  26.82 17.951 26.91 17.959 ;
     RECT  31.896 17.851 31.914 17.987 ;
     RECT  10.368 17.887 18.99 17.995 ;
     RECT  22.716 17.887 22.842 18.023 ;
     RECT  1.728 17.851 9.414 18.031 ;
     RECT  10.368 17.995 19.062 18.031 ;
     RECT  26.028 17.995 26.046 18.031 ;
     RECT  26.784 17.959 26.91 18.031 ;
     RECT  22.788 18.023 22.842 18.059 ;
     RECT  26.028 18.031 26.91 18.059 ;
     RECT  38.736 17.947 39.33 18.059 ;
     RECT  1.728 18.031 19.062 18.139 ;
     RECT  1.404 18.139 19.062 18.149 ;
     RECT  22.788 18.059 22.806 18.149 ;
     RECT  24.015 17.725 24.894 18.149 ;
     RECT  26.028 18.059 26.874 18.149 ;
     RECT  24.015 18.149 24.786 18.185 ;
     RECT  0.108 17.693 0.126 18.221 ;
     RECT  1.404 18.149 18.897 18.221 ;
     RECT  40.215 17.693 40.497 18.283 ;
     RECT  28.872 17.609 30.294 18.293 ;
     RECT  40.104 18.283 40.497 18.329 ;
     RECT  10.836 18.221 18.897 18.419 ;
     RECT  27.648 17.951 27.666 18.419 ;
     RECT  28.872 18.293 29.697 18.419 ;
     RECT  36.468 18.283 36.486 18.455 ;
     RECT  42.192 18.193 42.21 18.461 ;
     RECT  1.404 18.221 9.846 18.491 ;
     RECT  37.584 18.235 37.602 18.491 ;
     RECT  6.84 18.491 9.846 18.563 ;
     RECT  30.492 18.427 30.726 18.571 ;
     RECT  10.836 18.419 17.55 18.689 ;
     RECT  26.136 18.149 26.874 18.689 ;
     RECT  12.96 18.689 17.55 18.725 ;
     RECT  29.304 18.419 29.697 18.725 ;
     RECT  39.312 18.059 39.33 18.749 ;
     RECT  42.948 17.947 43.146 18.749 ;
     RECT  8.928 18.563 9.846 18.761 ;
     RECT  10.836 18.689 12.114 18.761 ;
     RECT  12.96 18.725 15.102 18.761 ;
     RECT  30.492 18.571 30.798 18.761 ;
     RECT  30.564 18.761 30.798 18.797 ;
     RECT  38.16 18.715 38.178 18.797 ;
     RECT  30.636 18.797 30.762 18.833 ;
     RECT  1.404 18.491 5.922 18.869 ;
     RECT  13.215 18.761 15.102 18.893 ;
     RECT  15.84 18.725 17.55 18.959 ;
     RECT  27.36 18.841 27.45 18.959 ;
     RECT  43.092 18.749 43.146 18.959 ;
     RECT  43.128 18.959 43.146 18.995 ;
     RECT  9.396 18.761 9.846 19.031 ;
     RECT  17.136 18.959 17.514 19.031 ;
     RECT  18.288 18.419 18.897 19.031 ;
     RECT  27.432 18.959 27.45 19.067 ;
     RECT  2.196 18.869 5.922 19.103 ;
     RECT  17.496 19.031 17.514 19.103 ;
     RECT  30.744 18.833 30.762 19.103 ;
     RECT  5.904 19.103 5.922 19.139 ;
     RECT  13.215 18.893 14.922 19.229 ;
     RECT  6.84 18.563 8.097 19.237 ;
     RECT  13.215 19.229 14.85 19.265 ;
     RECT  10.836 18.761 11.394 19.337 ;
     RECT  18.36 19.031 18.897 19.337 ;
     RECT  15.84 18.959 15.858 19.373 ;
     RECT  2.196 19.103 4.554 19.499 ;
     RECT  11.376 19.337 11.394 19.571 ;
     RECT  6.804 19.237 8.097 20.111 ;
     RECT  9.396 19.031 9.81 20.651 ;
     RECT  5.112 20.623 5.13 20.759 ;
     RECT  9.396 20.651 9.414 20.921 ;
     RECT  1.404 18.869 1.422 21.299 ;
     RECT  2.196 19.499 4.374 21.425 ;
     RECT  2.268 21.425 4.374 21.461 ;
     RECT  13.215 19.265 14.562 21.533 ;
     RECT  7.092 20.111 8.097 21.901 ;
     RECT  6.804 21.901 8.097 21.929 ;
     RECT  6.804 21.929 6.822 22.001 ;
     RECT  0.036 18.715 0.054 22.037 ;
     RECT  2.268 21.461 4.23 22.037 ;
     RECT  13.215 21.533 14.022 22.109 ;
     RECT  2.268 22.037 4.014 22.199 ;
     RECT  2.268 22.199 2.97 22.379 ;
     RECT  13.215 22.109 13.698 22.379 ;
     RECT  2.304 22.379 2.97 22.469 ;
     RECT  2.304 22.469 2.697 22.775 ;
     RECT  2.415 22.775 2.697 40.787 ;
     RECT  7.815 21.929 8.097 40.787 ;
     RECT  13.215 22.379 13.497 40.787 ;
     RECT  18.615 19.337 18.897 40.787 ;
     RECT  24.015 18.185 24.297 40.787 ;
     RECT  29.415 18.725 29.697 40.787 ;
     RECT  34.815 15.863 35.097 40.787 ;
     RECT  40.215 18.329 40.497 40.787 ;
     RECT  2.415 40.787 2.505 41.057 ;
     RECT  7.815 40.787 7.905 41.057 ;
     RECT  13.215 40.787 13.305 41.057 ;
     RECT  18.615 40.787 18.705 41.057 ;
     RECT  24.015 40.787 24.105 41.057 ;
     RECT  29.415 40.787 29.505 41.057 ;
     RECT  34.815 40.787 34.905 41.057 ;
     RECT  40.215 40.787 40.305 41.057 ;
    LAYER M4 ;
     RECT  0.012 14.016 0.025 18.936 ;
     RECT  0.025 13.92 2.293 18.936 ;
     RECT  0.012 8.64 2.408 9.048 ;
     RECT  2.293 13.92 2.408 19.32 ;
     RECT  2.293 20.592 2.408 20.616 ;
     RECT  2.408 2.148 2.512 41.052 ;
     RECT  2.512 2.418 2.704 40.782 ;
     RECT  2.704 13.92 2.765 18.264 ;
     RECT  2.704 19.968 2.765 20.616 ;
     RECT  2.765 19.968 2.819 20.088 ;
     RECT  2.704 21.696 2.819 21.72 ;
     RECT  2.704 10.848 2.837 10.872 ;
     RECT  2.765 13.92 2.837 18.216 ;
     RECT  2.819 19.968 2.867 19.992 ;
     RECT  2.837 13.92 2.909 15.192 ;
     RECT  2.909 13.92 2.945 13.944 ;
     RECT  2.837 16.368 2.981 18.216 ;
     RECT  2.981 16.368 3.053 18.168 ;
     RECT  3.053 16.368 3.197 17.064 ;
     RECT  2.909 15.024 4.021 15.192 ;
     RECT  3.053 18.096 4.237 18.168 ;
     RECT  4.165 9.072 4.259 9.096 ;
     RECT  4.237 18.096 4.525 18.216 ;
     RECT  3.197 17.04 4.561 17.064 ;
     RECT  4.021 15.024 4.669 15.624 ;
     RECT  4.561 16.8 4.669 17.064 ;
     RECT  4.525 18.096 4.705 18.408 ;
     RECT  4.669 15.024 5.077 17.064 ;
     RECT  4.021 13.536 5.141 13.56 ;
     RECT  5.077 14.64 5.285 17.064 ;
     RECT  5.285 14.64 5.641 14.664 ;
     RECT  4.705 18.096 5.825 18.456 ;
     RECT  5.285 15.984 6.181 17.064 ;
     RECT  5.825 18.096 6.181 18.216 ;
     RECT  6.181 15.984 6.365 18.216 ;
     RECT  5.641 14.448 6.685 14.664 ;
     RECT  6.365 15.984 6.685 18.168 ;
     RECT  6.685 14.448 7.808 18.168 ;
     RECT  7.808 2.148 7.912 41.052 ;
     RECT  7.912 2.418 8.104 40.782 ;
     RECT  8.104 13.92 9.029 18.168 ;
     RECT  9.029 15.744 9.301 18.168 ;
     RECT  9.301 15.744 9.388 18.408 ;
     RECT  10.748 1.728 10.835 1.752 ;
     RECT  9.388 15.744 11.413 18.168 ;
     RECT  11.413 15.744 11.909 18.408 ;
     RECT  9.029 13.92 12.517 14.664 ;
     RECT  11.909 15.744 12.517 18.168 ;
     RECT  12.517 13.92 13.208 18.168 ;
     RECT  13.208 2.148 13.312 41.052 ;
     RECT  13.312 2.418 13.504 40.782 ;
     RECT  13.504 13.92 14.497 14.472 ;
     RECT  13.504 15.696 14.825 18.888 ;
     RECT  14.825 15.744 15.113 18.888 ;
     RECT  14.497 13.92 16.081 14.664 ;
     RECT  16.081 13.92 16.193 14.712 ;
     RECT  15.113 15.744 16.373 18.168 ;
     RECT  16.193 13.92 17.269 14.664 ;
     RECT  16.373 15.744 17.269 18.072 ;
     RECT  17.269 13.92 18.608 18.072 ;
     RECT  18.608 2.148 18.712 41.052 ;
     RECT  18.712 2.418 18.904 40.782 ;
     RECT  18.904 13.92 19.721 16.968 ;
     RECT  19.721 15.552 20.333 16.968 ;
     RECT  19.721 13.92 21.193 14.568 ;
     RECT  20.333 15.552 21.193 15.816 ;
     RECT  21.193 13.92 21.917 15.816 ;
     RECT  21.917 14.16 22.133 15.816 ;
     RECT  22.133 14.256 22.453 15.816 ;
     RECT  20.333 16.944 22.453 16.968 ;
     RECT  22.453 14.256 22.885 16.968 ;
     RECT  22.885 14.256 23.033 17.112 ;
     RECT  22.501 9.024 23.497 9.048 ;
     RECT  23.497 8.784 24.008 9.048 ;
     RECT  23.033 14.256 24.008 15.816 ;
     RECT  23.033 17.088 24.008 17.112 ;
     RECT  24.008 2.148 24.112 41.052 ;
     RECT  24.112 2.418 24.304 40.782 ;
     RECT  24.304 14.448 24.581 14.472 ;
     RECT  24.304 15.744 25.121 17.112 ;
     RECT  25.121 15.744 25.877 16.392 ;
     RECT  25.877 15.792 26.809 16.392 ;
     RECT  26.809 15.792 26.845 16.68 ;
     RECT  26.809 17.856 26.845 17.88 ;
     RECT  26.845 15.792 26.957 17.88 ;
     RECT  24.304 8.688 29.408 9.048 ;
     RECT  25.945 14.208 29.408 14.232 ;
     RECT  26.957 15.792 29.408 16.536 ;
     RECT  29.408 2.148 29.512 41.052 ;
     RECT  29.512 2.418 29.704 40.782 ;
     RECT  29.704 8.688 34.808 9.048 ;
     RECT  29.704 14.208 34.808 14.232 ;
     RECT  29.704 15.84 34.808 16.536 ;
     RECT  34.808 2.148 34.912 41.052 ;
     RECT  34.912 2.418 35.104 40.782 ;
     RECT  35.104 15.84 37.573 16.536 ;
     RECT  36.457 18.288 37.573 18.312 ;
     RECT  37.573 15.84 37.609 17.208 ;
     RECT  37.573 18.24 37.609 18.312 ;
     RECT  37.609 15.84 38.149 18.312 ;
     RECT  35.104 8.688 38.513 9.048 ;
     RECT  35.104 14.208 39.301 14.232 ;
     RECT  38.149 15.84 39.841 18.744 ;
     RECT  39.301 14.208 39.913 14.52 ;
     RECT  39.841 15.504 39.913 18.744 ;
     RECT  38.513 8.688 40.208 8.712 ;
     RECT  39.913 14.208 40.208 18.744 ;
     RECT  40.208 2.148 40.312 41.052 ;
     RECT  40.312 2.418 40.504 40.782 ;
     RECT  40.504 8.64 41.857 8.664 ;
     RECT  40.504 14.208 42.181 18.744 ;
     RECT  42.181 14.112 43.081 18.744 ;
     RECT  43.081 14.112 43.117 18.936 ;
     RECT  41.857 8.64 43.2 9.048 ;
     RECT  43.117 14.016 43.2 18.936 ;
    LAYER M5 ;
     RECT  2.4 2.137 2.52 2.151 ;
     RECT  13.2 2.137 13.32 2.151 ;
     RECT  18.6 2.137 18.72 2.151 ;
     RECT  24 2.137 24.12 2.151 ;
     RECT  29.4 2.137 29.52 2.151 ;
     RECT  34.8 2.137 34.92 2.151 ;
     RECT  40.2 2.137 40.32 2.151 ;
     RECT  4.224 9.061 4.248 13.525 ;
     RECT  4.224 13.525 5.112 13.571 ;
     RECT  7.8 2.137 8.664 13.955 ;
     RECT  18.6 2.151 18.912 14.149 ;
     RECT  24 2.151 24.312 14.437 ;
     RECT  13.2 2.151 13.512 14.485 ;
     RECT  23.712 14.437 24.312 14.579 ;
     RECT  5.088 13.571 5.112 14.675 ;
     RECT  12.528 14.485 13.512 15.491 ;
     RECT  20.304 14.485 20.328 15.683 ;
     RECT  7.8 13.955 8.112 15.973 ;
     RECT  11.232 14.629 11.256 16.019 ;
     RECT  22.512 9.013 22.536 16.019 ;
     RECT  13.2 15.491 13.512 16.021 ;
     RECT  18.432 14.149 18.912 16.259 ;
     RECT  7.68 15.973 8.112 16.549 ;
     RECT  5.136 15.589 5.16 16.835 ;
     RECT  11.424 16.117 11.448 17.317 ;
     RECT  13.2 16.021 14.232 17.411 ;
     RECT  10.8 17.317 11.448 17.651 ;
     RECT  40.2 2.151 40.512 17.941 ;
     RECT  2.4 2.151 2.712 18.085 ;
     RECT  6.432 17.989 6.456 18.131 ;
     RECT  7.488 16.549 8.112 18.131 ;
     RECT  2.4 18.085 2.856 18.133 ;
     RECT  9.312 17.077 9.336 18.419 ;
     RECT  11.424 17.651 11.448 18.419 ;
     RECT  39.216 17.941 40.512 18.755 ;
     RECT  43.056 18.469 43.08 18.755 ;
     RECT  14.784 17.605 14.808 18.851 ;
     RECT  2.304 18.133 2.856 20.003 ;
     RECT  2.304 20.003 2.808 20.627 ;
     RECT  2.4 20.627 2.808 21.731 ;
     RECT  2.4 21.731 2.712 41.049 ;
     RECT  7.8 18.131 8.112 41.049 ;
     RECT  13.2 17.411 13.512 41.049 ;
     RECT  18.6 16.259 18.912 41.049 ;
     RECT  24 14.579 24.312 41.049 ;
     RECT  29.4 2.151 29.712 41.049 ;
     RECT  34.8 2.151 35.112 41.049 ;
     RECT  40.2 18.755 40.512 41.049 ;
     RECT  2.4 41.049 2.52 41.063 ;
     RECT  7.8 41.049 7.92 41.063 ;
     RECT  13.2 41.049 13.32 41.063 ;
     RECT  18.6 41.049 18.72 41.063 ;
     RECT  24 41.049 24.12 41.063 ;
     RECT  29.4 41.049 29.52 41.063 ;
     RECT  34.8 41.049 34.92 41.063 ;
     RECT  40.2 41.049 40.32 41.063 ;
     RECT  22.536 9.013 24 14.437 ;
     RECT  2.712 9.061 4.224 13.571 ;
     RECT  22.536 14.437 23.712 14.579 ;
     RECT  18.912 14.485 20.304 15.683 ;
     RECT  22.536 14.579 24 16.019 ;
     RECT  11.256 14.629 12.528 15.491 ;
     RECT  11.256 15.491 11.448 16.019 ;
     RECT  11.232 16.019 11.448 16.117 ;
     RECT  11.232 16.117 11.424 17.317 ;
     RECT  8.112 17.077 9.312 18.419 ;
     RECT  9.336 17.317 10.8 17.651 ;
     RECT  13.512 17.411 14.232 17.605 ;
     RECT  13.512 17.605 14.784 18.851 ;
     RECT  6.456 17.989 7.488 18.131 ;
  END
END ot_hgi_sm_pub_stream_edge
END LIBRARY
